VERSION 5.7 ;
  NOWIREEXTENSIONATPIN ON ;
  DIVIDERCHAR "/" ;
  BUSBITCHARS "[]" ;
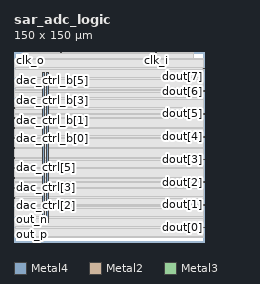
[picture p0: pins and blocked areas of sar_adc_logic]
MACRO sar_adc_logic
  CLASS BLOCK ;
  FOREIGN sar_adc_logic ;
  ORIGIN 0.000 0.000 ;
  SIZE 150.000 BY 150.000 ;
  PIN VDD
    DIRECTION INOUT ;
    USE POWER ;
    PORT
      LAYER Metal4 ;
        RECT 22.240 15.380 23.840 133.580 ;
    END
  END VDD
  PIN VSS
    DIRECTION INOUT ;
    USE GROUND ;
    PORT
      LAYER Metal4 ;
        RECT 25.540 15.380 27.140 133.580 ;
    END
  END VSS
  PIN clk_i
    DIRECTION INPUT ;
    USE SIGNAL ;
    ANTENNAGATEAREA 0.675500 ;
    PORT
      LAYER Metal2 ;
        RECT 112.000 149.440 112.560 150.000 ;
    END
  END clk_i
  PIN clk_o
    DIRECTION OUTPUT ;
    USE SIGNAL ;
    ANTENNADIFFAREA 9.462399 ;
    PORT
      LAYER Metal3 ;
        RECT 0.000 144.480 0.560 145.040 ;
    END
  END clk_o
  PIN dac_ctrl[0]
    DIRECTION OUTPUT ;
    USE SIGNAL ;
    ANTENNADIFFAREA 0.897600 ;
    PORT
      LAYER Metal3 ;
        RECT 0.000 19.040 0.560 19.600 ;
    END
  END dac_ctrl[0]
  PIN dac_ctrl[1]
    DIRECTION OUTPUT ;
    USE SIGNAL ;
    ANTENNADIFFAREA 0.897600 ;
    PORT
      LAYER Metal3 ;
        RECT 0.000 26.880 0.560 27.440 ;
    END
  END dac_ctrl[1]
  PIN dac_ctrl[2]
    DIRECTION OUTPUT ;
    USE SIGNAL ;
    ANTENNADIFFAREA 0.897600 ;
    PORT
      LAYER Metal3 ;
        RECT 0.000 34.720 0.560 35.280 ;
    END
  END dac_ctrl[2]
  PIN dac_ctrl[3]
    DIRECTION OUTPUT ;
    USE SIGNAL ;
    ANTENNADIFFAREA 0.897600 ;
    PORT
      LAYER Metal3 ;
        RECT 0.000 42.560 0.560 43.120 ;
    END
  END dac_ctrl[3]
  PIN dac_ctrl[4]
    DIRECTION OUTPUT ;
    USE SIGNAL ;
    ANTENNADIFFAREA 0.897600 ;
    PORT
      LAYER Metal3 ;
        RECT 0.000 50.400 0.560 50.960 ;
    END
  END dac_ctrl[4]
  PIN dac_ctrl[5]
    DIRECTION OUTPUT ;
    USE SIGNAL ;
    ANTENNADIFFAREA 0.897600 ;
    PORT
      LAYER Metal3 ;
        RECT 0.000 58.240 0.560 58.800 ;
    END
  END dac_ctrl[5]
  PIN dac_ctrl[6]
    DIRECTION OUTPUT ;
    USE SIGNAL ;
    ANTENNADIFFAREA 0.897600 ;
    PORT
      LAYER Metal3 ;
        RECT 0.000 66.080 0.560 66.640 ;
    END
  END dac_ctrl[6]
  PIN dac_ctrl[7]
    DIRECTION OUTPUT ;
    USE SIGNAL ;
    ANTENNADIFFAREA 0.897600 ;
    PORT
      LAYER Metal3 ;
        RECT 0.000 73.920 0.560 74.480 ;
    END
  END dac_ctrl[7]
  PIN dac_ctrl_b[0]
    DIRECTION OUTPUT ;
    USE SIGNAL ;
    ANTENNADIFFAREA 0.897600 ;
    PORT
      LAYER Metal3 ;
        RECT 0.000 81.760 0.560 82.320 ;
    END
  END dac_ctrl_b[0]
  PIN dac_ctrl_b[1]
    DIRECTION OUTPUT ;
    USE SIGNAL ;
    ANTENNADIFFAREA 0.897600 ;
    PORT
      LAYER Metal3 ;
        RECT 0.000 89.600 0.560 90.160 ;
    END
  END dac_ctrl_b[1]
  PIN dac_ctrl_b[2]
    DIRECTION OUTPUT ;
    USE SIGNAL ;
    ANTENNADIFFAREA 0.897600 ;
    PORT
      LAYER Metal3 ;
        RECT 0.000 97.440 0.560 98.000 ;
    END
  END dac_ctrl_b[2]
  PIN dac_ctrl_b[3]
    DIRECTION OUTPUT ;
    USE SIGNAL ;
    ANTENNADIFFAREA 0.897600 ;
    PORT
      LAYER Metal3 ;
        RECT 0.000 105.280 0.560 105.840 ;
    END
  END dac_ctrl_b[3]
  PIN dac_ctrl_b[4]
    DIRECTION OUTPUT ;
    USE SIGNAL ;
    ANTENNADIFFAREA 0.897600 ;
    PORT
      LAYER Metal3 ;
        RECT 0.000 113.120 0.560 113.680 ;
    END
  END dac_ctrl_b[4]
  PIN dac_ctrl_b[5]
    DIRECTION OUTPUT ;
    USE SIGNAL ;
    ANTENNADIFFAREA 0.897600 ;
    PORT
      LAYER Metal3 ;
        RECT 0.000 120.960 0.560 121.520 ;
    END
  END dac_ctrl_b[5]
  PIN dac_ctrl_b[6]
    DIRECTION OUTPUT ;
    USE SIGNAL ;
    ANTENNADIFFAREA 0.897600 ;
    PORT
      LAYER Metal3 ;
        RECT 0.000 128.800 0.560 129.360 ;
    END
  END dac_ctrl_b[6]
  PIN dac_ctrl_b[7]
    DIRECTION OUTPUT ;
    USE SIGNAL ;
    ANTENNADIFFAREA 0.897600 ;
    PORT
      LAYER Metal3 ;
        RECT 0.000 136.640 0.560 137.200 ;
    END
  END dac_ctrl_b[7]
  PIN dout[0]
    DIRECTION OUTPUT ;
    USE SIGNAL ;
    ANTENNADIFFAREA 0.897600 ;
    PORT
      LAYER Metal3 ;
        RECT 149.440 11.200 150.000 11.760 ;
    END
  END dout[0]
  PIN dout[1]
    DIRECTION OUTPUT ;
    USE SIGNAL ;
    ANTENNADIFFAREA 0.897600 ;
    PORT
      LAYER Metal3 ;
        RECT 149.440 29.120 150.000 29.680 ;
    END
  END dout[1]
  PIN dout[2]
    DIRECTION OUTPUT ;
    USE SIGNAL ;
    ANTENNADIFFAREA 0.897600 ;
    PORT
      LAYER Metal3 ;
        RECT 149.440 47.040 150.000 47.600 ;
    END
  END dout[2]
  PIN dout[3]
    DIRECTION OUTPUT ;
    USE SIGNAL ;
    ANTENNADIFFAREA 0.897600 ;
    PORT
      LAYER Metal3 ;
        RECT 149.440 64.960 150.000 65.520 ;
    END
  END dout[3]
  PIN dout[4]
    DIRECTION OUTPUT ;
    USE SIGNAL ;
    ANTENNADIFFAREA 0.897600 ;
    PORT
      LAYER Metal3 ;
        RECT 149.440 82.880 150.000 83.440 ;
    END
  END dout[4]
  PIN dout[5]
    DIRECTION OUTPUT ;
    USE SIGNAL ;
    ANTENNADIFFAREA 0.897600 ;
    PORT
      LAYER Metal3 ;
        RECT 149.440 100.800 150.000 101.360 ;
    END
  END dout[5]
  PIN dout[6]
    DIRECTION OUTPUT ;
    USE SIGNAL ;
    ANTENNADIFFAREA 0.897600 ;
    PORT
      LAYER Metal3 ;
        RECT 149.440 118.720 150.000 119.280 ;
    END
  END dout[6]
  PIN dout[7]
    DIRECTION OUTPUT ;
    USE SIGNAL ;
    ANTENNADIFFAREA 0.897600 ;
    PORT
      LAYER Metal3 ;
        RECT 149.440 136.640 150.000 137.200 ;
    END
  END dout[7]
  PIN out_n
    DIRECTION INPUT ;
    USE SIGNAL ;
    ANTENNAGATEAREA 0.396000 ;
    PORT
      LAYER Metal3 ;
        RECT 0.000 11.200 0.560 11.760 ;
    END
  END out_n
  PIN out_p
    DIRECTION INPUT ;
    USE SIGNAL ;
    ANTENNAGATEAREA 0.498500 ;
    PORT
      LAYER Metal3 ;
        RECT 0.000 3.360 0.560 3.920 ;
    END
  END out_p
  PIN rst_n
    DIRECTION INPUT ;
    USE SIGNAL ;
    ANTENNAGATEAREA 4.408000 ;
    PORT
      LAYER Metal2 ;
        RECT 36.960 149.440 37.520 150.000 ;
    END
  END rst_n
  OBS
      LAYER Nwell ;
        RECT 6.290 15.250 143.230 133.710 ;
      LAYER Metal1 ;
        RECT 6.720 15.380 142.800 133.580 ;
      LAYER Metal2 ;
        RECT 7.420 149.140 36.660 149.440 ;
        RECT 37.820 149.140 111.700 149.440 ;
        RECT 112.860 149.140 141.540 149.440 ;
        RECT 7.420 3.450 141.540 149.140 ;
      LAYER Metal3 ;
        RECT 0.860 144.180 149.440 144.900 ;
        RECT 0.560 137.500 149.440 144.180 ;
        RECT 0.860 136.340 149.140 137.500 ;
        RECT 0.560 129.660 149.440 136.340 ;
        RECT 0.860 128.500 149.440 129.660 ;
        RECT 0.560 121.820 149.440 128.500 ;
        RECT 0.860 120.660 149.440 121.820 ;
        RECT 0.560 119.580 149.440 120.660 ;
        RECT 0.560 118.420 149.140 119.580 ;
        RECT 0.560 113.980 149.440 118.420 ;
        RECT 0.860 112.820 149.440 113.980 ;
        RECT 0.560 106.140 149.440 112.820 ;
        RECT 0.860 104.980 149.440 106.140 ;
        RECT 0.560 101.660 149.440 104.980 ;
        RECT 0.560 100.500 149.140 101.660 ;
        RECT 0.560 98.300 149.440 100.500 ;
        RECT 0.860 97.140 149.440 98.300 ;
        RECT 0.560 90.460 149.440 97.140 ;
        RECT 0.860 89.300 149.440 90.460 ;
        RECT 0.560 83.740 149.440 89.300 ;
        RECT 0.560 82.620 149.140 83.740 ;
        RECT 0.860 82.580 149.140 82.620 ;
        RECT 0.860 81.460 149.440 82.580 ;
        RECT 0.560 74.780 149.440 81.460 ;
        RECT 0.860 73.620 149.440 74.780 ;
        RECT 0.560 66.940 149.440 73.620 ;
        RECT 0.860 65.820 149.440 66.940 ;
        RECT 0.860 65.780 149.140 65.820 ;
        RECT 0.560 64.660 149.140 65.780 ;
        RECT 0.560 59.100 149.440 64.660 ;
        RECT 0.860 57.940 149.440 59.100 ;
        RECT 0.560 51.260 149.440 57.940 ;
        RECT 0.860 50.100 149.440 51.260 ;
        RECT 0.560 47.900 149.440 50.100 ;
        RECT 0.560 46.740 149.140 47.900 ;
        RECT 0.560 43.420 149.440 46.740 ;
        RECT 0.860 42.260 149.440 43.420 ;
        RECT 0.560 35.580 149.440 42.260 ;
        RECT 0.860 34.420 149.440 35.580 ;
        RECT 0.560 29.980 149.440 34.420 ;
        RECT 0.560 28.820 149.140 29.980 ;
        RECT 0.560 27.740 149.440 28.820 ;
        RECT 0.860 26.580 149.440 27.740 ;
        RECT 0.560 19.900 149.440 26.580 ;
        RECT 0.860 18.740 149.440 19.900 ;
        RECT 0.560 12.060 149.440 18.740 ;
        RECT 0.860 10.900 149.140 12.060 ;
        RECT 0.560 4.220 149.440 10.900 ;
        RECT 0.860 3.500 149.440 4.220 ;
  END
END sar_adc_logic
END LIBRARY

